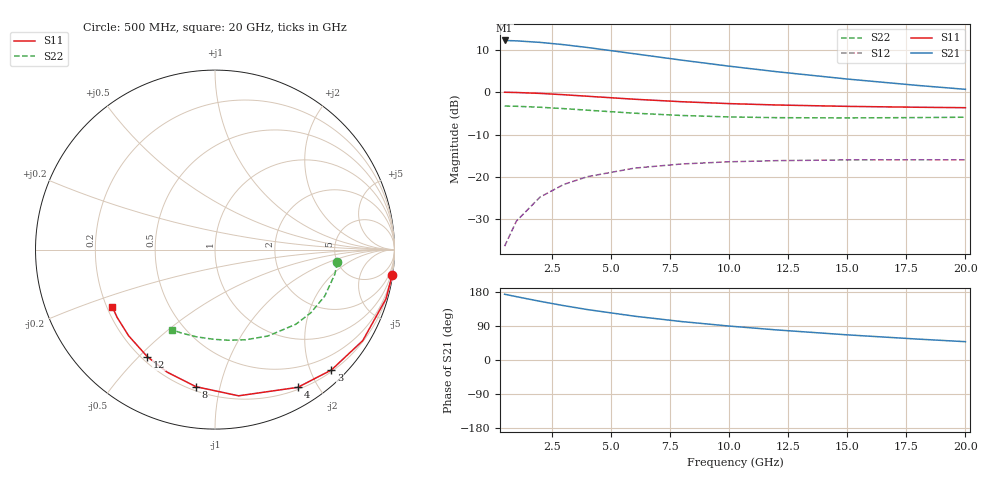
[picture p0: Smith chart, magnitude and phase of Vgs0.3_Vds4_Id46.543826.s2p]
# Hz S RI R 50
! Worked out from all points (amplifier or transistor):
!   12 points, 500 MHz to 20 GHz, reference 50 ohm
!   highest |S21| = 12.2 dB at 500 MHz (marker M1)
!   |S21| within 3 dB of that: start of sweep to 5.805 GHz
!   unconditionally stable (mu >= 1): 18.37 GHz to end of sweep
!   at 2 GHz: K = 0.10, MSG = 18.3 dB, |S12| = -24.8 dB
!   at 8 GHz: K = 0.41, MSG = 12.2 dB, |S12| = -16.9 dB
!   at 20 GHz: K = 1.10, MAG = 6.4 dB, |S12| = -16.0 dB
!   S11 on the Smith chart (normalised r, x): 500 MHz: 0, -14; 3 GHz: 0.23, -2.34; 4 GHz: 0.23, -1.75; 8 GHz: 0.22, -0.84; 12 GHz: 0.22, -0.53; 20 GHz: 0.22, -0.25
5e8  0.9878 -0.1407  -4.051 0.4578  0.00146 0.0151  0.6825 -0.0708
1e9  0.9521 -0.2753  -3.932 0.8952  0.00572 0.0296  0.667 -0.139
2e9  0.8234 -0.5069  -3.503 1.643  0.0211 0.0538  0.6109 -0.2598
3e9  0.6484 -0.6708  -2.922 2.164  0.0418 0.0699  0.5337 -0.3522
4e9  0.4612 -0.7674  -2.303 2.458  0.0638 0.0777  0.4497 -0.4163
6e9  0.1313 -0.8146  -1.226 2.56  0.1016 0.0761  0.2944 -0.4817
8e9  -0.1066 -0.7636  -0.4709 2.339  0.1275 0.0629  0.1708 -0.5024
1e10  -0.2675 -0.6822  0.015 2.027  0.1433 0.0468  0.0738 -0.5049
1.2e10  -0.3766 -0.5972  0.3201 1.716  0.1524 0.0311  -0.00563 -0.5
1.5e10  -0.4812 -0.4803  0.5728 1.309  0.1583 0.0102  -0.1049 -0.4856
1.8e10  -0.5444 -0.3794  0.6862 0.984  0.1592 -0.00695  -0.1889 -0.4643
2e10  -0.5725 -0.3198  0.7182 0.8072  0.1582 -0.0167  -0.2387 -0.4464
